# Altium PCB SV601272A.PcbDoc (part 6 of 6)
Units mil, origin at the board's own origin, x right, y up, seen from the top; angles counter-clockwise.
Board outline 8300 x 9520 mil, 8 copper layers (Top Layer, Signal Layer 1, Signal Layer 2, Signal Layer 3, Signal Layer 4, Signal Layer 5, Signal Layer 6, Bottom Layer), stack 59.2 mil thick; 551 components, 303 nets, 1611 pads, 1923 vias.

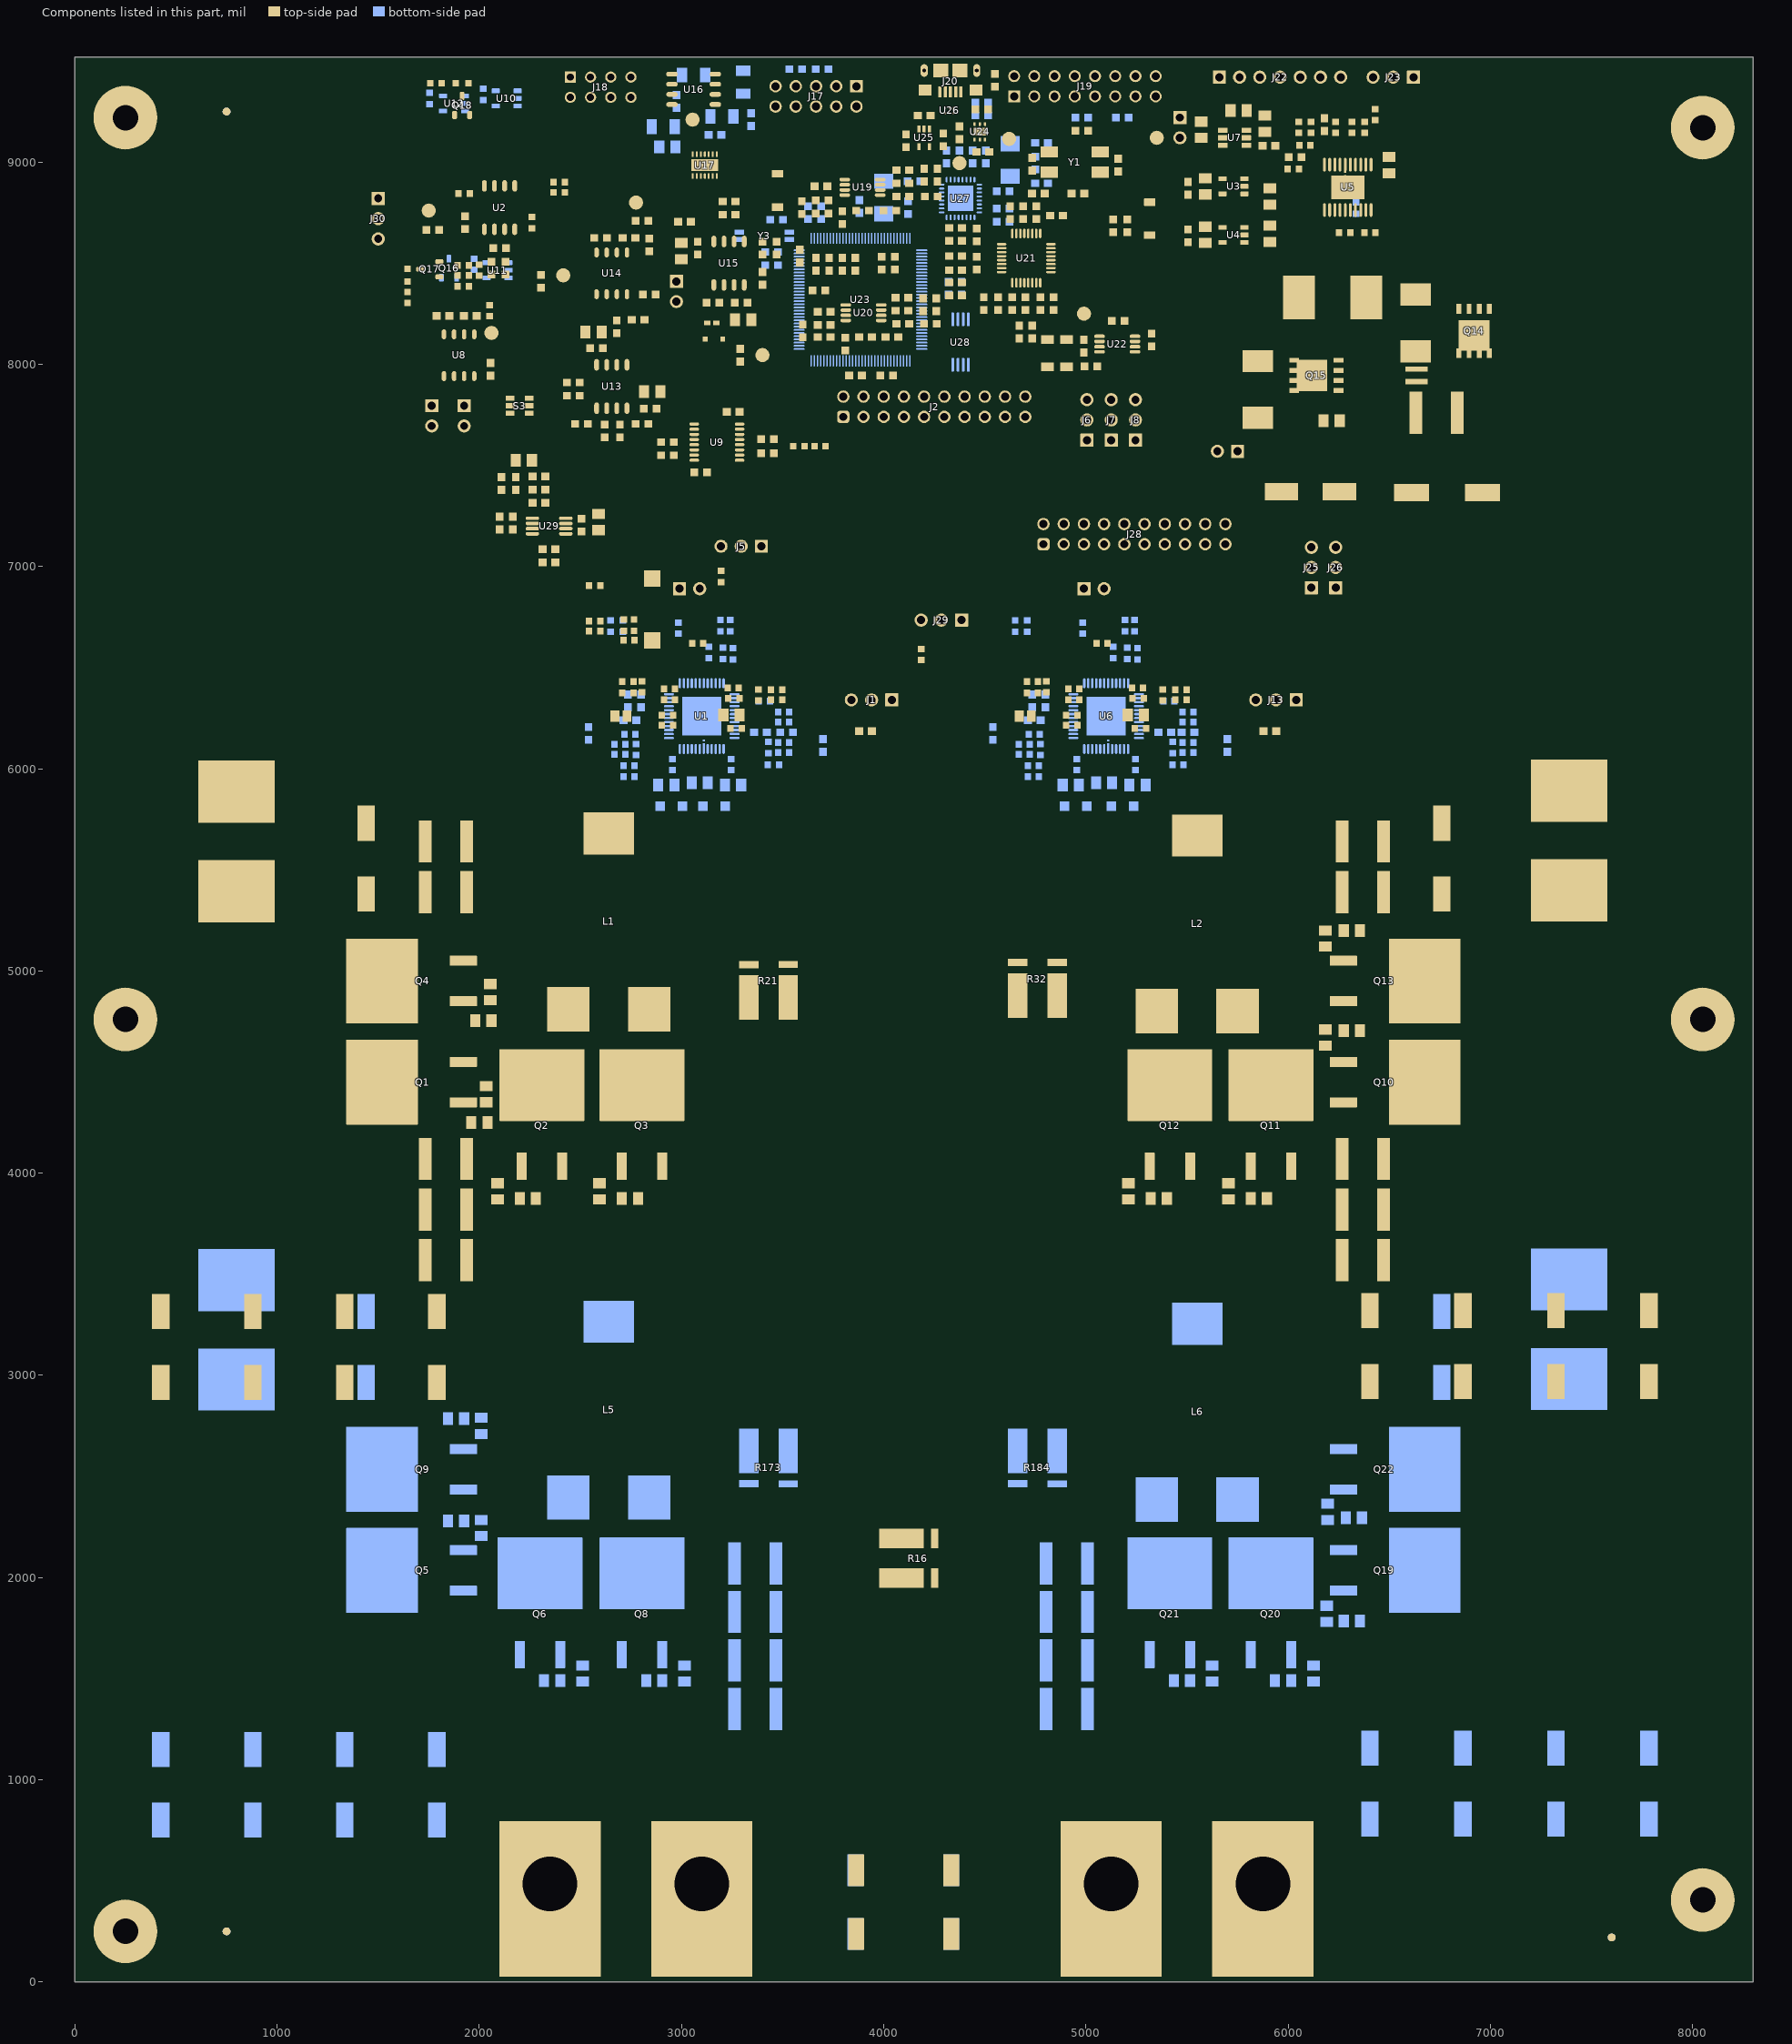
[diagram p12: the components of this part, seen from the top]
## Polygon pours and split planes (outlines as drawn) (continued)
NetC42_1 on Top Layer "NETC42_1_L01_P6041" (solid, remove dead copper, pour order 6041): 5715,7275 5715,7790 6200,7790 6200,7665 6200,7605 6070,7475 6065,7470 6065,7275
SW4 on Top Layer "SW4_L01_P6056" (solid, remove dead copper, pour order 6056): 5520,2735 5520,2285 5473.67,2238.67 5108.67,2238.67 5070,2200 5070,1865 5116.33,1818.67 6308.67,1818.67 6350,1860 6350,2745 6316.33,2778.67 5563.67,2778.67
SW3 on Top Layer "SW3_L01_P6058" (solid, remove dead copper, pour order 6058): 3180,1845 3180,2205 3143.26,2241.74 2716.74,2241.74 2670,2288.49 2670,2755 2653.26,2771.74 1886.74,2771.74 1850,2735 1850,1850 1888.26,1811.74 3146.74,1811.74
V_HV on Top Layer "V_HV_L01_P6060" (solid, remove dead copper, pour order 6060): 1840,945 1000,945 1000,3135 1840,3135
I_TOTAL on Top Layer "I_TOTAL_L01_P6053" (solid, remove dead copper, pour order 6053): 3460,4755 3460,5235 4730,5235 4730,4755
NetL5_1 on Top Layer "NETL5_1_L01_P6048" (solid, remove dead copper, pour order 6048): 2720,2275 3370,2275 3395,2300 3395,2740 3370,2765 2720,2765 2700,2745 2700,2295
V_LV on Top Layer "V_LV_L01_P6061" (solid, remove dead copper, pour order 6061): 5462,30.26 4699.74,30.26 4365,365 3800,365 3420,745 3420,2075 4885,2075 4885,1295 5462,718
AGND on Top Layer "AGND_L01_P6064" (solid, remove dead copper, pour order 6064): 2469.97,9500 1425,9500 1425,6070 6615,6070 6615,9500
PGND on Top Layer "PGND_L01_P6065" (solid, remove dead copper, pour order 6065): 0,0 0,9520 8320,9520 8320,0
V_LV on Signal Layer 3 "V_LV_L04_P6117" (solid, remove dead copper, pour order 6117): 3925,1565 4275,1565 4275,945 3925,945
V_HV on Signal Layer 3 "V_HV_L04_P6124" (solid, remove dead copper, pour order 6124): 8300,5850 6850,5850 6850,7525 6800,7575 6800,7920 6800,7945 6775,7970 6775,8240 8300,8240
V_HV on Signal Layer 3 "V_HV_L04_P6118" (solid, remove dead copper, pour order 6118): 7080,7215 6850,7215 6850,7520 6800,7570 6800,7915 6800,7940 6775,7965 6775,8235 7080,8235
SW4 on Signal Layer 3 "SW4_L04_P6120" (solid, remove dead copper, pour order 6120): 5495,2680 5495,2228.67 5113.67,2228.67 5070,2185 5070,1845 5106.33,1808.67 6133.67,1808.67 6170,1845 6170,2685 6135,2720 5535,2720
SW3 on Signal Layer 3 "SW3_L04_P6122" (solid, remove dead copper, pour order 6122): 3150,1845 3150,2215 3120,2245 2700,2245 2670,2275 2670,2695 2635,2730 2035,2730 2002.64,2697.64 2002.64,1842.36 2030,1815 3120,1815
SW2 on Signal Layer 3 "SW2_L04_P6121" (solid, remove dead copper, pour order 6121): 5495,5095 5495,4643.67 5113.67,4643.67 5070,4600 5070,4260 5106.33,4223.67 6133.67,4223.67 6170,4260 6170,5100 6135,5135 5535,5135
SW1 on Signal Layer 3 "SW1_L04_P6123" (solid, remove dead copper, pour order 6123): 3180,4250 3180,4620 3150,4650 2730,4650 2700,4680 2700,5100 2665,5135 2065,5135 2032.64,5102.64 2032.64,4247.36 2060,4220 3150,4220
I_TOTAL on Signal Layer 3 "I_TOTAL_L04_P6119" (solid, remove dead copper, pour order 6119): 3465,5235 4695,5235 4710,5220 4710,4755 3465,4755
V_HV on Signal Layer 3 "V_HV_L04_P6125" (solid, remove dead copper, pour order 6125): 0,0 0,5945 8300,5945 8300,67.21
PGND on Signal Layer 3 "PGND_L04_P6126" (solid, remove dead copper, pour order 6126): 5797.48,9495 7280,9495 7280,5965 0,5965 0,9495 2472.33,9495 1485,9495 1485,7905 2487.75,7905 3627.33,6765.42 3630.03,6768.12 4646.91,6768.12 4646.91,6770 5795.11,7918.19
AGND on Signal Layer 3 "AGND_L04_P6127" (solid, remove dead copper, pour order 6127): 2469.97,9500 1285,9500 1285,6070 6615,6070 6615,9500
V_LV on Signal Layer 4 "V_LV_L05_P6145" (solid, remove dead copper, pour order 6145): 3925,1555 4275,1555 4275,945 3925,945
V_HV on Signal Layer 4 "V_HV_L05_P6144" (solid, remove dead copper, pour order 6144): 6857.3,2740.55 6857.3,2330.55 6482.3,2330.55 6482.3,2740.55
V_HV on Signal Layer 4 "V_HV_L05_P6140" (solid, remove dead copper, pour order 6140): 6857.3,2240.55 6857.3,1830.55 6482.3,1830.55 6482.3,2240.55
V_HV on Signal Layer 4 "V_HV_L05_P6142" (solid, remove dead copper, pour order 6142): 1715,2240 1715,1830 1340,1830 1340,2240
V_HV on Signal Layer 4 "V_HV_L05_P6141" (solid, remove dead copper, pour order 6141): 1335.92,2329.37 1335.92,2739.37 1710.92,2739.37 1710.92,2329.37
SW3 on Signal Layer 4 "SW3_L05_P6135" (solid, remove dead copper, pour order 6135): 2114,2209 2476,2209 2500,2185 2500,1855 2479,1834 2111,1834 2090,1855 2090,2185
SW3 on Signal Layer 4 "SW3_L05_P6133" (solid, remove dead copper, pour order 6133): 2624,2209 2986,2209 3010,2185 3010,1855 2989,1834 2621,1834 2600,1855 2600,2185
SW4 on Signal Layer 4 "SW4_L05_P6129" (solid, remove dead copper, pour order 6129): 5735,2210 6095,2210 6120,2185 6120,1855 6100,1835 5730,1835 5710,1855 5710,2185
SW4 on Signal Layer 4 "SW4_L05_P6131" (solid, remove dead copper, pour order 6131): 5235,2210 5595,2210 5620,2185 5620,1855 5600,1835 5230,1835 5210,1855 5210,2185
DGND on Signal Layer 4 "DGND_L05_P6147" (solid, remove dead copper, pour order 6147): 4100,9420 4100,9270 3990,9270 3975,9255 3975,9220 3400,9220 3350,9170 3350,9070 3200,9070 3200,7895 4700,7895 4700,7970 4700,8620 4900,8620 4900,8770 5050,8770 5050,9270 4600,9270 4600,9420
NetD6_2 on Signal Layer 4 "Signal Layer 2-No Net 3" (solid, pour order 6128): 6215,7820 5750,7820 5750,8095 6215,8095
V_HV on Signal Layer 4 "V_HV_L05_P6146" (solid, remove dead copper, pour order 6146): 7074.74,7222.72 6844.74,7222.72 6844.74,7527.72 6794.74,7577.72 6794.74,7922.72 6794.74,7947.72 6769.74,7972.72 6769.74,8242.72 7074.74,8242.72
SW2 on Signal Layer 4 "SW2_L05_P6132" (solid, remove dead copper, pour order 6132): 5235,4625 5595,4625 5620,4600 5620,4270 5600,4250 5230,4250 5210,4270 5210,4600
SW2 on Signal Layer 4 "SW2_L05_P6130" (solid, remove dead copper, pour order 6130): 5735,4625 6095,4625 6120,4600 6120,4270 6100,4250 5730,4250 5710,4270 5710,4600
SW1 on Signal Layer 4 "SW1_L05_P6134" (solid, remove dead copper, pour order 6134): 2624,4624 2986,4624 3010,4600 3010,4270 2989,4249 2621,4249 2600,4270 2600,4600
SW1 on Signal Layer 4 "SW1_L05_P6136" (solid, remove dead copper, pour order 6136): 2114,4624 2476,4624 2500,4600 2500,4270 2479,4249 2111,4249 2090,4270 2090,4600
V_HV on Signal Layer 4 "V_HV_L05_P6138" (solid, remove dead copper, pour order 6138): 1335.92,4744.37 1335.92,5154.37 1710.92,5154.37 1710.92,4744.37
V_HV on Signal Layer 4 "V_HV_L05_P6143" (solid, remove dead copper, pour order 6143): 1715,4655 1715,4245 1340,4245 1340,4655
V_HV on Signal Layer 4 "V_HV_L05_P6139" (solid, remove dead copper, pour order 6139): 6857.3,4655.55 6857.3,4245.55 6482.3,4245.55 6482.3,4655.55
V_HV on Signal Layer 4 "V_HV_L05_P6137" (solid, remove dead copper, pour order 6137): 6857.3,5155.55 6857.3,4745.55 6482.3,4745.55 6482.3,5155.55
AGND on Signal Layer 4 "AGND_L05_P6148" (solid, remove dead copper, pour order 6148): 2469.97,9500 1425,9500 1425,6070 6615,6070 6615,9500
PGND on Signal Layer 4 "PGND_L05_P6149" (solid, remove dead copper, pour order 6149): 0,0 0,9520 8300,9520 8300,0
I_TOTAL on Signal Layer 6 "I_TOTAL_L07_P6182" (solid, remove dead copper, pour order 6182): 4675,5240 4675,2330 3855,2330 3855,5240
I_TOTAL on Signal Layer 6 "I_TOTAL_L07_P6181" (solid, remove dead copper, pour order 6181): 3460,2335 4725,2335 4730,2340 4730,2820 3460,2820
V_LV on Signal Layer 6 "V_LV_L07_P6179" (solid, remove dead copper, pour order 6179): 3925,2075 4275,2075 4275,1235 3925,1235
V_HV on Signal Layer 6 "V_HV_L07_P6178" (solid, remove dead copper, pour order 6178): 6855,5155 6855,4745 6480,4745 6480,5155
V_HV on Signal Layer 6 "V_HV_L07_P6172" (solid, remove dead copper, pour order 6172): 1710,4655 1710,4245 1335,4245 1335,4655
V_HV on Signal Layer 6 "V_HV_L07_P6175" (solid, remove dead copper, pour order 6175): 1715,5155 1715,4745 1340,4745 1340,5155
V_HV on Signal Layer 6 "V_HV_L07_P6173" (solid, remove dead copper, pour order 6173): 6858.58,4655 6858.58,4245 6483.58,4245 6483.58,4655
SW2 on Signal Layer 6 "SW2_L07_P6164" (solid, remove dead copper, pour order 6164): 5738.58,4618.58 6091.42,4618.58 6120,4590 6120,4270 6093.58,4243.58 5736.42,4243.58 5710,4270 5710,4590
SW2 on Signal Layer 6 "SW2_L07_P6165" (solid, remove dead copper, pour order 6165): 5238.58,4618.58 5591.42,4618.58 5620,4590 5620,4270 5593.58,4243.58 5236.42,4243.58 5210,4270 5210,4590
SW1 on Signal Layer 6 "SW1_L07_P6167" (solid, remove dead copper, pour order 6167): 2121.77,4616.77 2478.23,4616.77 2505,4590 2505,4265 2481.77,4241.77 2123.23,4241.77 2095,4270 2095,4590
SW1 on Signal Layer 6 "SW1_L07_P6170" (solid, remove dead copper, pour order 6170): 2625,4615 2985,4615 3010,4590 3010,4265 2985,4240 2625,4240 2600,4265 2600,4590
SW3 on Signal Layer 6 "SW3_L07_P6169" (solid, remove dead copper, pour order 6169): 2625,2200 2985,2200 3010,2175 3010,1850 2985,1825 2625,1825 2600,1850 2600,2175
SW3 on Signal Layer 6 "SW3_L07_P6168" (solid, remove dead copper, pour order 6168): 2121.77,2201.77 2478.23,2201.77 2505,2175 2505,1850 2481.77,1826.77 2123.23,1826.77 2095,1855 2095,2175
SW4 on Signal Layer 6 "SW4_L07_P6166" (solid, remove dead copper, pour order 6166): 5238.58,2203.58 5591.42,2203.58 5620,2175 5620,1855 5593.58,1828.58 5236.42,1828.58 5210,1855 5210,2175
SW4 on Signal Layer 6 "SW4_L07_P6163" (solid, remove dead copper, pour order 6163): 5738.58,2203.58 6091.42,2203.58 6120,2175 6120,1855 6093.58,1828.58 5736.42,1828.58 5710,1855 5710,2175
V_HV on Signal Layer 6 "V_HV_L07_P6171" (solid, remove dead copper, pour order 6171): 6858.58,2240 6858.58,1830 6483.58,1830 6483.58,2240
V_HV on Signal Layer 6 "V_HV_L07_P6176" (solid, remove dead copper, pour order 6176): 1715,2740 1715,2330 1340,2330 1340,2740
V_HV on Signal Layer 6 "V_HV_L07_P6174" (solid, remove dead copper, pour order 6174): 1710,2240 1710,1830 1335,1830 1335,2240
V_HV on Signal Layer 6 "V_HV_L07_P6177" (solid, remove dead copper, pour order 6177): 6855,2740 6855,2330 6480,2330 6480,2740
I_TOTAL on Signal Layer 6 "I_TOTAL_L07_P6180" (solid, remove dead copper, pour order 6180): 3460,4755 3460,5235 4730,5235 4730,4755
AGND on Signal Layer 6 "AGND_L07_P6183" (solid, remove dead copper, pour order 6183): 2469.97,9500 1425,9500 1425,6070 6615,6070 6615,9500
PGND on Signal Layer 6 "PGND_L07_P6184" (solid, remove dead copper, pour order 6184): 0,0 0,9520 8300,9520 8300,0
V_LV on Signal Layer 5 "V_LV_L06_P6154" (solid, remove dead copper, pour order 6154): 3925,1535 4275,1535 4275,955 3925,955
SW3 on Signal Layer 5 "SW3_L06_P6158" (solid, remove dead copper, pour order 6158): 3340,1845 3340,2195 3300,2235 2690,2235 2690,2665 2635,2720 2080,2720 2032.64,2672.64 2032.64,1862.36 2090,1805 3300,1805
SW4 on Signal Layer 5 "SW4_L06_P6156" (solid, remove dead copper, pour order 6156): 5510,2685 5510,2228.67 4993.67,2228.67 4950,2185 4950,1855 4996.33,1808.67 6123.67,1808.67 6170,1855 6170,2685 6130,2725 5550,2725
SW2 on Signal Layer 5 "SW2_L06_P6155" (solid, remove dead copper, pour order 6155): 5510,5100 5510,4643.67 4993.67,4643.67 4950,4600 4950,4270 4996.33,4223.67 6123.67,4223.67 6170,4270 6170,5100 6130,5140 5550,5140
SW1 on Signal Layer 5 "SW1_L06_P6157" (solid, remove dead copper, pour order 6157): 3340,4260 3340,4610 3300,4650 2690,4650 2690,5080 2635,5135 2080,5135 2032.64,5087.64 2032.64,4277.36 2090,4220 3300,4220
V_HV on Signal Layer 5 "V_HV_L06_P6150" (solid, remove dead copper, pour order 6150): 1711.28,4654.45 1711.28,4244.45 1336.28,4244.45 1336.28,4654.45
V_HV on Signal Layer 5 "Signal Layer 3-No Net 2" (solid, remove dead copper, pour order 6151): 1711.28,5154.45 1711.28,4744.45 1336.28,4744.45 1336.28,5154.45
V_HV on Signal Layer 5 "Signal Layer 3-No Net 2" (solid, remove dead copper, pour order 6153): 6855,4655 6855,4245 6480,4245 6480,4655
V_HV on Signal Layer 5 "Signal Layer 3-No Net 2" (solid, remove dead copper, pour order 6152): 6855,5155 6855,4745 6480,4745 6480,5155
V_HV on Signal Layer 5 "V_HV_L06_P6160" (solid, remove dead copper, pour order 6160): 7730,0 0,0 0,3070 7730,3070
V_HV on Signal Layer 5 "V_HV_L06_P6161" (solid, remove dead copper, pour order 6161): 8300,2615 0,2615 0,5685 8300,5685
AGND on Signal Layer 5 "AGND_L06_P6159" (solid, remove dead copper, pour order 6159): 2469.97,9500 1425,9500 1425,6070 6615,6070 6615,9500
PGND on Signal Layer 5 "PGND_L06_P6162" (solid, remove dead copper, pour order 6162): 0,-1055 0,9520 8300,9520 8300,-1055

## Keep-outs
Keep-Out Layer:
  lines w10: 0,0 8300,0 8300,9530 0,9530 0,0
  text ".Layer_Name" at -823,-3938.49 h60

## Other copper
Top Layer:
  rectangle net V_HV: 1650,5500 1840,5770
  rectangle net PGND: 6215,8815 6535,8940
  pour cut-out: 3450,2275 3400,2275 3400,2605 3450,2605 3450,2325
  pour cut-out: 4230,4690 3400,4690 3400,5005 3450,5005 3450,4740 4230,4740
  pour cut-out: 6625,7940 6645,7940 6655,7930 6655,7910 6645,7900 6625,7900 6615,7910 6615,7930
  pour cut-out: 6200,8705 6220,8705 6230,8695 6230,8675 6220,8665 6200,8665 6190,8675 6190,8695
  pour cut-out: 6230.97,8700.64 6220,8700.64 6220,8805 6236.74,8805 6245,8796.74 6245,8714.67
  pour cut-out: 2035,-40 2035,855 2670,855 2670,-40
  region net V_HV: 7030,7020 7030,7570 6850,7750 6850,7850 7210,7850 7210,7020
  region net PGND: 6150,7275 6700,7275 6700,7875 6325,7875 6275,7825 6225,7775 6225,7475 6200,7450 6150,7450
  pour cut-out: 3960,4695 4790,4695 4790,5010 4740,5010 4740,4745 3960,4745
  pour cut-out: 4790,2275 4740,2275 4740,2605 4790,2605 4790,2325
  text ".Layer_Name" at -823,-3938.49 h60
Signal Layer 1:
  pour cut-out: 6625,7940 6645,7940 6655,7930 6655,7910 6645,7900 6625,7900 6615,7910 6615,7930
  pour cut-out: 6200,8705 6220,8705 6230,8695 6230,8675 6220,8665 6200,8665 6190,8675 6190,8695
  text ".Layer_Name" at -825,-3935 h60
Signal Layer 2:
  pour cut-out: 6625,7940 6645,7940 6655,7930 6655,7910 6645,7900 6625,7900 6615,7910 6615,7930
  pour cut-out: 6200,8705 6220,8705 6230,8695 6230,8675 6220,8665 6200,8665 6190,8675 6190,8695
  text ".Layer_Name" at -825,-3935 h60
Signal Layer 3:
  rectangle net I_TOTAL: 3570,2360 4560,2760
  rectangle net AGND: 5000,6155 5200,6360
  rectangle net AGND: 3000,6155 3205,6360
  pour cut-out: 6625,7940 6645,7940 6655,7930 6655,7910 6645,7900 6625,7900 6615,7910 6615,7930
  pour cut-out: 6200,8705 6220,8705 6230,8695 6230,8675 6220,8665 6200,8665 6190,8675 6190,8695
  text ".Layer_Name" at -825,-3935 h60
Signal Layer 4:
  rectangle net I_TOTAL: 4400,2360 4560,2780
  rectangle net I_TOTAL: 3570,2360 3915,2755
  region: 1720,4862.56
  pour cut-out: 6625,7940 6645,7940 6655,7930 6655,7910 6645,7900 6625,7900 6615,7910 6615,7930
  pour cut-out: 6200,8705 6220,8705 6230,8695 6230,8675 6220,8665 6200,8665 6190,8675 6190,8695
  text ".Layer_Name" at -825,-3935 h60
Signal Layer 5:
  region net I_TOTAL: 4395,5235 4395,4705 4330,4640 4330,2095 4675,2095 4675,5235
  region net V_LV: 3925,955 4300,955 4300,1550 3925,1550
  region net I_TOTAL: 3900,2090 3575,2090 3575,5235 3900,5235
  pour cut-out: 6200,8705 6220,8705 6230,8695 6230,8675 6220,8665 6200,8665 6190,8675 6190,8695
  text ".layer_Name" at -820,-3940 h60
Signal Layer 6:
  region net V_LV: 3925,1215 4275,1215 4275,1550 3925,1550
  region net I_TOTAL: 3900,2330 3575,2330 3575,5240 3900,5240
  pour cut-out: 6200,8705 6220,8705 6230,8695 6230,8675 6220,8665 6200,8665 6190,8675 6190,8695
  text ".layer_Name" at -820,-3940 h60
Bottom Layer:
  rectangle net AGND: 5082.61,6143.07 5142.61,6168.07
  rectangle net AGND: 3082.61,6143.07 3142.61,6168.07
  region net I_TOTAL: 3900,2335 3585,2335 3585,5235 3900,5235
  region net V_LV: 3922.5,640 4297.5,640 4297.5,1550 3922.5,1550
  pour cut-out: 6625,7940 6645,7940 6655,7930 6655,7910 6645,7900 6625,7900 6615,7910 6615,7930
  pour cut-out: 6200,8705 6220,8705 6230,8695 6230,8675 6220,8665 6200,8665 6190,8675 6190,8695
  text ".Layer_Name" at -823,-3938.49 h60
Multi-Layer:
  region: 1670,2647.56
  region: 1670,5062.56

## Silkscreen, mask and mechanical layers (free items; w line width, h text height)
Top Overlay:
  rectangle: 1355,7360 1655,7460
  lines w8: 2785,6310 2840,6310 2855,6295 ; 2855,6295 2845.11,6295 2855,6304.89 2855,6295
  text "BUCK MODE" at 1635,9445 h28
  text "AGND" at 6730,9405 h72.83
  text "RESET" at 5600,9335 h40
  text "TDO" at 5725,9335 h40
  text "TDI" at 5830,9335 h40
  text "TMS" at 5925,9335 h40
  text "TCK" at 6025,9335 h40
  text "RX" at 6135,9335 h40
  text "TX" at 6240,9335 h40
  text "IREF" at 2375,9315 h72.83 r90
  text "VREF" at 2865,9285 h72.83 r90
  text "MISO" at 4605,9240 h40
  text "MOSI" at 4705,9240 h40
  text "CS" at 4820,9240 h40
  text "SCLK" at 4895,9240 h40
  text "DRDY" at 4995,9240 h40
  text "DONE" at 5100,9240 h40
  text "AGND" at 5205,9240 h40
  text "AGND" at 5315,9240 h35
  text "AGND" at 1435,8620 h72.83 r90
  text "CC" at 2955,8385 h28
  text "BOOST MODE" at 1555,8240 h28 r90
  text "V5A" at 1630,8140 h28 r90
  text "N" at 5365,7810 h28 r90
  text "BOOST" at 4910,7750 h28 r90
  text "NFAULT" at 3830,7650 h40
  text "SYNCOUT" at 4015,7650 h40
  text "ISETA" at 4250,7650 h40
  text "UVLO" at 4455,7650 h40
  text "OVPA" at 4655,7650 h40
  text "OPT" at 3750,7620 h40
  text "OVPB" at 4555,7620 h40
  text "IOUT2" at 4155,7615 h40
  text "SYNCIN" at 4330,7615 h40
  text "Y" at 5365,7615 h28 r90
  text "IOUT1" at 3955,7610 h40
  text "CV" at 1740,7585 h28
  text "BUCK" at 4910,7580 h28 r90
  text "VLV" at 1940,7545 h28 r90
  text "VHV" at 2095,7540 h28 r90
  text "DIR" at 4970,7500 h28
  text "EN1" at 5090,7500 h28
  text "EN2" at 5205,7500 h28
  text "V10-Aux" at 5600,7455 h28
  text "OPT" at 3025,7350 h28
  text "NFAULT2" at 4820,7020 h40
  text "SYNCOUT2" at 5005,7020 h40
  text "ISETA" at 5240,7020 h40
  text "UVLO" at 5445,7020 h40
  text "OVPA2" at 5645,7020 h40
  text "SYNC_OUT" at 2920,7010 h28
  text "OPT2" at 4740,6990 h40
  text "OVPB2" at 5545,6990 h40
  text "IOUT4" at 5145,6985 h40
  text "SYNCIN2" at 5320,6985 h40
  text "IOUT3" at 4945,6980 h40
  text "EN3" at 6080,6770 h28
  text "EN4" at 6195,6770 h28
  text "LV" at 5800,6415 h28
  text "HV" at 6020,6415 h28
  text "LV" at 3790,6410 h28
  text "UVLO" at 3885,6410 h28
  text "HV" at 4040,6410 h28
  text "V_HV" at 2580,3440 h80
  text "V_LV" at 5380,3435 h80
  text "-" at 3085,3390 h120
  text "+" at 2320,3385 h120
  text "-" at 5850,3385 h120
  text "+" at 5070,3370 h120
  text ".Layer_Name" at -823,-3938.49 h60
Bottom Overlay:
  text "J3" at 4150,7585 h28
  text "J5" at 3150,7440 h28
  text "OPT" at 3110,7350 h28
  text "J21" at 5210,6940 h28
  text "HV BIAS LV" at 6065,6415 h28
  text "HV VIN LV" at 4060,6410 h28
  text "J1" at 4155,6320 h28
  text "V_LV" at 5680,3445 h80
  text "V_HV" at 2880,3430 h80
  text "-" at 3165,3395 h120
  text "+" at 2400,3390 h120
  text "-" at 5935,3380 h120
  text "+" at 5155,3365 h120
  text ".Layer_Name" at -823,-3938.49 h60
Top Paste:
  text ".Layer_Name" at -823,-3938.49 h60
Bottom Paste:
  text ".Layer_Name" at -823,-3938.49 h60
Top Solder:
  text ".Layer_Name" at -823,-3938.49 h60
  text ".Layer_Name" at -823,-3938.49 h60
Bottom Solder:
  text ".Layer_Name" at -823,-3938.49 h60
Drill Guide:
  text ".Layer_Name" at -823,-3938.49 h60
M1 Board Outline:
  the board outline again, w10
  text ".Layer_Name" at -823,-3938.49 h60
M2 Board Dimensions:
  rectangle: -1275,-3480 -900,-3355
  rectangle: -1400,-3355 -1275,-3230
  lines w7: -1400,-3355 -400,-3355 ; -1275,-3480 -1275,-3230 ; -1150,-3480 -1150,-3230 ; -900,-3480 -900,-3230 ; -650,-3480 -650,-3230 ; -1400,-3480 -1400,-3230 -400,-3230 -400,-3480 -1400,-3480
  text ".Layer_Name" at -823,-3938.49 h60
M3 3D STEP Top:
  text ".Layer_Name" at -823,-3938.49 h60
M4 3D STEP Bottom:
  text ".Layer_Name" at -823,-3938.49 h60
M5 Assembly Top:
  lines w10: -1692,-4010.17 4908,-4010.17 ; -1692,-3806.83 4910,-3806.83 ; -1692,-3603.5 -1692,-4213.5 2313,-4213.5 4910,-4213.5 4910,-3603.5 -1691.5,-3603.5 -1691.5,-4213.5 -116,-4213.5 ; 773,-4213.5 773,-3603.5 ; 2040,-3806.83 2040,-3603.5 ; 2880,-3806.83 2880,-3603.5 ; 3502,-4220 3502,-4017.17
  text "COMPONENTS MARKED 'DNP' SHOULD NOT BE POPULATED." at -246.5,-3398.5 h60
  text "ASSEMBLY VARIANT:" at -247,-3514 h60
  text ".VariantName" at 789,-3514 h60
  text "PCB VIEWED FROM TOP SIDE" at -1628.5,-3735.67 h60
  text "BOARD #:" at 848,-3735.67 h60
  text ".PRJ_Number" at 1393.5,-3735.67 h60
  text "REV:" at 2238,-3735.67 h60
  text ".PCB_Rev" at 2529.5,-3735.67 h60
  text ".VersionControl_RevNumber" at 3582,-3735.67 h60
  text "SVN REV:" at 2313.19,-3776.26 h60
  text "PLOT NAME =" at -1628.5,-4144.34 h60
  text ".plot_File_Name" at -823,-4144.34 h60
  text "GENERATED    :" at 850,-4144.34 h60
  text ".Print_Date" at 1719.5,-4144.34 h60
  text ".Print_Time" at 2448.5,-4144.34 h60
  text "TEXAS INSTRUMENTS" at 3713,-4144.34 h60
M6 Assembly Bottom:
  lines w10: -1692.5,-3807.33 4909.5,-3807.33 ; -1690.5,-4010.67 4909.5,-4010.67 ; -284.5,-4220.5 -284.5,-4017.67 ; 337.5,-3807.33 337.5,-3604 ; 1177.5,-3807.33 1177.5,-3604 ; 2444.5,-4214 2444.5,-3604 ; 3333.5,-4214 4909,-4214 4909,-3604 -1692.5,-3604 -1692.5,-4214 904.5,-4214 4909.5,-4214 4909.5,-3604
  text "COMPONENTS MARKED 'DNP' SHOULD NOT BE POPULATED." at 4702,-3398 h60
  text ".VariantName" at 3658,-3514 h60
  text "ASSEMBLY VARIANT:" at 4697,-3514 h60
  text ".VersionControl_RevNumber" at -364.5,-3736.17 h60
  text "SVN REV:" at 141.5,-3736.17 h60
  text ".PCB_Rev" at 688,-3736.17 h60
  text "REV:" at 979.5,-3736.17 h60
  text ".PRJ_Number" at 1824,-3736.17 h60
  text "BOARD #:" at 2369.5,-3736.17 h60
  text "PCB VIEWED FROM BOTTOM SIDE" at 4846,-3736.17 h60
  text "TEXAS INSTRUMENTS" at -495.5,-4144.84 h60
  text ".Print_Time" at 769,-4144.84 h60
  text ".Print_Date" at 1498,-4144.84 h60
  text "GENERATED    :" at 2367.5,-4144.84 h60
  text ".plot_File_Name" at 4040.5,-4144.84 h60
  text "PLOT NAME =" at 4846,-4144.84 h60
M9 Title Sheet:
  drawing of 57 lines, arcs and shapes, not listed
  text "1" at -660.16,4956.5 h70
  text "2" at 1835.5,4956.5 h70
  text "3" at 4324.84,4956.5 h70
  text "4" at 4831.51,4956.5 h70
  text "5" at 7330.5,4956.5 h70
  text "6" at 9835.5,4956.5 h70
  text "A" at -1816.5,3813.5 h70
  text "A" at 12983.5,3813.5 h70
  text "B" at -1816.5,1433.5 h70
  text "B" at 12983.5,1433.5 h70
  text "C" at -1816.5,-941.5 h70
  text "C" at 12983.5,-941.5 h70
  text "PROJECT TITLE:" at 9943.5,-2802.5 h45
  text ".PRJ_Title" at 9993.5,-2935.83 h70
  text "DESIGNED FOR:" at 9943.5,-3103.5 h45
  text ".PRJ_Customer" at 9993.5,-3243.5 h70
  text "D" at -1816.5,-3311.5 h70
  text "D" at 12983.5,-3311.5 h70
  text "FILE NAME:" at 9943.5,-3403.5 h45
  text ".PCB_File_Name_No_Path" at 9993.5,-3523.5 h70
  text "Texas Instruments (TI) and/or its licensors do not warrant the accuracy or completeness of this specification" at 4974,-3685.34 h45
  text "ENGINEER:" at 9943.5,-3693.5 h45
  text "LAYOUT BY:" at 11448.5,-3693.5 h45
  text "or any information contained therein. TI and/or its licensors do not warrant that this design will meet" at 4929.01,-3798 h45
  text ".PRJ_Engineer" at 9993.5,-3848.49 h70
  text ".PCB_Layout" at 11499,-3848.49 h70
  text "the specifications, will be suitable for your application or fit for any particular purpose, or will operate in" at 4929.01,-3910.67 h45
  text ".Layer_Name" at -823,-3938.49 h60
  text "ALTIUM DESIGNER VERSION:" at 11448.5,-4003.5 h45
  text "an implementation. TI and/or its licensors do not warrant that the design is production worthy. You should" at 4929.01,-4023.33 h45
  text "completely validate and test your design implementation to confirm the system functionality for your application." at 4974,-4136 h45
  text ".print_Scale" at 9993.5,-4136.83 h70
  text ".Application_BuildNumber" at 11499,-4136.83 h70
  text "1" at -660.16,-4343.5 h70
  text "2" at 1835.5,-4343.5 h70
  text "3" at 4324.84,-4343.5 h70
  text "4" at 6831.51,-4343.5 h70
  text "5" at 9330.5,-4343.5 h70
  text "6" at 11835.5,-4343.5 h70
M10 Fab Notes:
  drawing of 185 lines, arcs and shapes, not listed
  text "DESIGN INFORMATION" at 10981.02,2830 h60
  text "MIN. TRACK WIDTH:" at 10336.46,2650 h60
  text "8" at 11432.7,2650 h60
  text "MIL" at 11587.46,2650 h60
  text "MIN. CLEARANCE:" at 10336.46,2518 h60
  text "0.2" at 11372.7,2518 h60
  text "mm" at 11587.46,2518 h60
  text "MIN. VIA PAD SIZE:" at 10336.46,2386 h60
  text "24" at 11402.71,2386 h60
  text "MIL" at 11587.46,2386 h60
  text "0.05mm (2MIL)" at 11031.46,2244.29 h60
  text "MINIMUM ANNULAR RING" at 10007.23,2240 h60
  text "EXTERNAL" at 11739.46,2240 h60
  text "PER" at 10207.23,2122 h60
  text "IPC-D-275 CLASS 2 LEVEL C" at 10427.23,2122 h60
  text "MIL, HOLES" at 11915.46,2009.71 h60
  text "+/-" at 11523,2009 h60
  text "+/-" at 12377,2009 h60
  text "REGISTRATION TOLERANCES:" at 10007.23,2004 h60
  text "METAL" at 11207,2004 h60
  text "5" at 11783.2,2004 h60
  text "3" at 12616.2,2004 h60
  text "MIL" at 12732.46,2004 h60
  text "MATERIAL:" at 9932.46,1794.54 h60
  text "FR-4 High Tg" at 10918.9,1654.21 h60
  text "FR-408" at 10353.46,1645.64 h60
  text "X" at 10765.46,1645.64 h60
  text "OTHER" at 11841.46,1645.64 h60
  text "62 MIL (1.6mm) +/-10%" at 10673.56,1482.92 h60
  text "THICKNESS:" at 10007.23,1478.64 h60
  text "X" at 10545.4,1478.64 h60
  text "OTHER" at 11958.46,1478.64 h60
  text "TOLERANCE:" at 8862.23,1320.64 h60
  text "X" at 10846.53,1320.64 h60
  text "ANSI IPC-6012 TYPE 3 CLASS 2" at 11033.48,1320.64 h60
  text "OTHER +/-" at 11033.46,1164.64 h60
  text "BOW & TWIST:" at 10007.23,1007.64 h60
  text "X" at 10846.53,1007.64 h60
  text "ANSI IPC-6012 TYPE 3 CLASS 2" at 11033.48,1007.64 h60
  text "OTHER +/-" at 11033.46,849.13 h60
  text "DRILLING:" at 9932.46,710.64 h60
  text "REFERENCE:" at 10007.23,593.64 h60
  text "X" at 10655.46,593.64 h60
  text "AS SHOWN" at 10842.46,593.64 h60
  text "X" at 11556.46,593.64 h60
  text "NC_DRILL FILES" at 11693.46,593.64 h60
  text "PTH MIN COPPER THICKNESS:" at 10007.23,435.64 h60
  text "X" at 11357.46,435.64 h60
  text "1MIL" at 11494.46,435.64 h60
  text "OTHER" at 11991.46,435.64 h60
  text "BOARD FINISH:" at 9932.46,276.64 h60
  text "SILKSCREEN:" at 10087.68,158.64 h60
  text "X" at 11036.46,158.64 h60
  text "TOP" at 11162.46,158.64 h60
  text "X" at 11546.46,158.64 h60
  text "BOTTOM" at 11673.46,158.64 h60
  text "SILKSCREEN COLOR:" at 10087.68,-8.36 h60
  text "X" at 11035.42,-8.36 h60
  text "WHITE" at 11162.46,-8.36 h60
  text "OTHER" at 11673.46,-8.36 h60
  text "SOLDER RESIST COLOR:" at 10087.68,-178.36 h60
  text "X" at 10655.42,-337.56 h60
  text "GREEN" at 10782.46,-337.56 h60
  text "BLUE" at 11373.46,-337.56 h60
  text "OTHER" at 11911.46,-337.56 h60
  text "IMMERSION GOLD (ENIG)" at 10993.46,-526.08 h60
  text "ENEPIG" at 12331,-529.36 h60
  text "SURFACE FINISH:" at 9932.46,-530.36 h60
  text "X" at 10805,-535 h60
  text "IMM. TIN/SILVER OR EQUIV" at 10262,-687.36 h60
  text "OTHER" at 11693.46,-687.36 h60
  text "ARRAY/PANEL:" at 9932.46,-866.36 h60
  text "CUT AND TRIM PER MECH LAYER 1" at 10993.46,-870.65 h60
  text "N.C. ROUTE" at 10993.46,-1022.36 h60
  text "V. SCORE" at 11859.46,-1022.36 h60
  text "X" at 10800,-1025 h60
  text "CERTIFICATION:" at 9932.46,-1159.36 h60
  text "MATERIALS AND WORKMANSHIP FOR ALL PCBS" at 10657.46,-1159.36 h60
  text "TO MEET OR EXCEED THE REQUIREMENTS OF:" at 10657.46,-1257.36 h60
  text "X" at 10283.96,-1393.87 h60
  text "ANSI IPC-A-600F CLASS ->" at 10422.96,-1393.87 h60
  text "X" at 12062.02,-1393.87 h60
  text "2" at 12180.96,-1393.86 h60
  text "1" at 11865.96,-1395.36 h60
  text "3" at 12534.96,-1395.36 h60
  text "X" at 10286.02,-1553.36 h60
  text "UL 94V-0" at 10422.96,-1553.36 h60
  text "X" at 11098.02,-1553.36 h60
  text "RoHS" at 11234.96,-1553.36 h60
  text "OTHER" at 11879.36,-1553.36 h60
  text "PER ORDER" at 12276.42,-1553.36 h60
  text "ADDITIONAL REQUIREMENTS:" at 9932.46,-1694.36 h60
  text "MICROSECTION:" at 10007.23,-1809.36 h60
  text "YES" at 10912.96,-1809.36 h60
  text "REQUIRED" at 11774.46,-1965.51 h60
  text "BARE BOARD ELEC. TEST:" at 10007.23,-1968.36 h60
  text "NONE" at 11312.96,-1968.36 h60
  text "X" at 11647.46,-1968.36 h60
  text "PER ORDER" at 12366.46,-1968.36 h60
  text "MANUFACTURER'S UL:" at 10007.23,-2125.36 h60
  text "RAIL" at 11172.96,-2129.65 h60
  text "METAL" at 11664.77,-2129.65 h60
  text "X" at 12040,-2130 h60
  text "SILK" at 12176.46,-2129.65 h60
  text ".Layer_Name" at -823,-3938.49 h60
M11 Gerber Information:
  lines w10: -1692,-4010.17 4908,-4010.17 ; -1692,-3806.83 4910,-3806.83 ; -1692,-3603.5 -1692,-4213.5 2313,-4213.5 4910,-4213.5 4910,-3603.5 -1691.5,-3603.5 -1691.5,-4213.5 -116,-4213.5 ; 773,-4213.5 773,-3603.5 ; 2040,-3806.83 2040,-3603.5 ; 2880,-3806.83 2880,-3603.5 ; 3502,-4220 3502,-4017.17
  text "ALL ARTWORK VIEWED FROM TOP SIDE" at -1628.5,-3735.67 h60
  text "BOARD #:" at 848,-3735.67 h60
  text ".PRJ_Number" at 1393.5,-3735.67 h60
  text "REV:" at 2238,-3735.67 h60
  text ".PCB_Rev" at 2529.5,-3735.67 h60
  text ".VersionControl_RevNumber" at 3582,-3735.67 h60
  text "SVN REV:" at 2313.19,-3776.26 h60
  text "LAYER NAME =" at -1628.5,-3938.49 h60
  text "PLOT NAME =" at -1628.5,-4144.34 h60
  text ".plot_File_Name" at -823,-4144.34 h60
  text "GENERATED    :" at 850,-4144.34 h60
  text ".Print_Date" at 1719.5,-4144.34 h60
  text ".Print_Time" at 2448.5,-4144.34 h60
  text "TEXAS INSTRUMENTS" at 3713,-4144.34 h60
M12 Stackup:
  drawing of 503 lines, arcs and shapes, not listed
  text "Layer" at -484.42,12885 h60
  text "Name" at -74.51,12885 h60
  text "Material" at 865.23,12885 h60
  text "Thickness" at 1725,12885 h60
  text "Constant" at 2374.84,12885 h60
  text "Board Layer Stack" at 2944.7,12885 h60
  text "1" at -484.42,12765 h60
  text "Top Overlay" at -74.51,12765 h60
  text "2" at -484.42,12645 h60
  text "Top Solder" at -74.51,12645 h60
  text "Solder Resist" at 865.23,12645 h60
  text "0.40mil" at 1725,12645 h60
  text "3.5" at 2374.84,12645 h60
  text "3" at -484.42,12525 h60
  text "Top Layer" at -74.51,12525 h60
  text "Copper" at 865.23,12525 h60
  text "3.20mil" at 1725,12525 h60
  text "4" at -484.42,12405 h60
  text "Dielectric1" at -74.51,12405 h60
  text "FR-4" at 865.23,12405 h60
  text "5.00mil" at 1725,12405 h60
  text "4.8" at 2374.84,12405 h60
  text "5" at -484.42,12285 h60
  text "Signal Layer 1" at -74.51,12285 h60
  text "Copper" at 865.23,12285 h60
  text "2.80mil" at 1725,12285 h60
  text "6" at -484.42,12165 h60
  text "Dielectric 2" at -74.51,12165 h60
  text "FR-4" at 865.23,12165 h60
  text "5.00mil" at 1725,12165 h60
  text "4.2" at 2374.84,12165 h60
  text "7" at -484.42,12045 h60
  text "Signal Layer 2" at -74.51,12045 h60
  text "Copper" at 865.23,12045 h60
  text "2.80mil" at 1725,12045 h60
  text "8" at -484.42,11925 h60
  text "Dielectric 3" at -74.51,11925 h60
  text "FR-4" at 865.23,11925 h60
  text "5.00mil" at 1725,11925 h60
  text "4.2" at 2374.84,11925 h60
  text "9" at -484.42,11805 h60
  text "Signal Layer 3" at -74.51,11805 h60
  text "Copper" at 865.23,11805 h60
  text "2.80mil" at 1725,11805 h60
  text "10" at -484.42,11685 h60
  text "Dielectric4" at -74.51,11685 h60
  text "FR-4" at 865.23,11685 h60
  text "6.00mil" at 1725,11685 h60
  text "4.2" at 2374.84,11685 h60
  text "11" at -484.42,11565 h60
  text "Signal Layer 4" at -74.51,11565 h60
  text "Copper" at 865.23,11565 h60
  text "2.80mil" at 1725,11565 h60
  text "12" at -484.42,11445 h60
  text "Dielectric 5" at -74.51,11445 h60
  text "FR-4" at 865.23,11445 h60
  text "5.00mil" at 1725,11445 h60
  text "4.2" at 2374.84,11445 h60
  text "13" at -484.42,11325 h60
  text "Signal Layer 5" at -74.51,11325 h60
  text "Copper" at 865.23,11325 h60
  text "2.80mil" at 1725,11325 h60
  text "14" at -484.42,11205 h60
  text "Dielectric 6" at -74.51,11205 h60
  text "FR-4" at 865.23,11205 h60
  text "5.00mil" at 1725,11205 h60
  text "4.2" at 2374.84,11205 h60
  text "15" at -484.42,11085 h60
  text "Signal Layer 6" at -74.51,11085 h60
  text "Copper" at 865.23,11085 h60
  text "2.80mil" at 1725,11085 h60
  text "16" at -484.42,10965 h60
  text "Dielectric 7" at -74.51,10965 h60
  text "FR-4" at 865.23,10965 h60
  text "5.00mil" at 1725,10965 h60
  text "4.2" at 2374.84,10965 h60
  text "17" at -484.42,10845 h60
  text "Bottom Layer" at -74.51,10845 h60
  text "Copper" at 865.23,10845 h60
  text "3.20mil" at 1725,10845 h60
  text "18" at -484.42,10725 h60
  text "Bottom Solder" at -74.51,10725 h60
  text "Solder Resist" at 865.23,10725 h60
  text "0.40mil" at 1725,10725 h60
  text "3.5" at 2374.84,10725 h60
  text "19" at -484.42,10605 h60
  text "Bottom Overlay" at -74.51,10605 h60
  text ".Layer_Name" at -823,-3938.49 h60
M13 Component Bodies Top:
  text ".Layer_Name" at -823,-3938.49 h60
M14 Component Bodies Bottom:
  text ".Layer_Name" at -823,-3938.49 h60
M15 Courtyards Top:
  text ".Layer_Name" at -823,-3938.49 h60
M16 Courtyards Bottom:
  text ".Layer_Name" at -823,-3938.49 h60
Drill Drawing:
  circle w10: c5783.72,12092.65 r16.58
  circle w10: c5783.72,12092.65 r27.63
  circle w10: c5783.72,11844.01 r27.63
  lines w10: 5756.09,10946.14 5756.09,10959.96 5769.9,10973.77 5756.09,10987.58 5756.09,11001.4 5769.9,11001.4 5783.72,10987.58 5797.53,11001.4 5811.34,11001.4 5811.34,10987.58 5797.53,10973.77 5811.34,10959.96 5811.34,10946.14 5797.53,10946.14 5783.72,10959.96 5769.9,10946.14 5756.09,10946.14 ; 5756.09,11084.28 5769.9,11084.28 5769.9,11070.46 5797.53,11070.46 5797.53,11084.28 5811.34,11084.28 5811.34,11111.9 5797.53,11111.9 5797.53,11125.72 5769.9,11125.72 5769.9,11111.9 5756.09,11111.9 5756.09,11084.28 ; 5756.09,11208.6 5769.9,11208.6 5783.72,11194.78 5797.53,11208.6 5811.34,11208.6 5797.53,11222.41 5811.34,11236.22 5797.53,11236.22 5783.72,11250.04 5769.9,11236.22 5756.09,11236.22 5769.9,11222.41 5756.09,11208.6 ; 5756.09,11332.92 5769.9,11332.92 5769.9,11319.1 5797.53,11319.1 5797.53,11332.92 5811.34,11332.92 5811.34,11360.54 5797.53,11360.54 5797.53,11374.36 5769.9,11374.36 5769.9,11360.54 5756.09,11360.54 5756.09,11332.92 ; 5756.09,11443.42 5811.34,11443.42 5811.34,11498.68 5756.09,11498.68 5756.09,11443.42 ; 5756.09,11623 5811.34,11623 5783.72,11567.74 5756.09,11623 ; 5756.09,11692.06 5783.72,11705.88 5811.34,11692.06 5797.53,11719.69 5811.34,11747.32 5783.72,11733.5 5756.09,11747.32 5769.9,11719.69 5756.09,11692.06 ; 5756.09,11940.7 5811.34,11940.7 5811.34,11995.96 5756.09,11995.96 5756.09,11940.7 ; 5756.09,12341.29 5783.72,12313.66 5811.34,12341.29 5783.72,12368.92 5756.09,12341.29 ; 5756.09,12686.62 5756.09,12700.44 5769.9,12714.25 5756.09,12728.06 5756.09,12741.88 5769.9,12741.88 5783.72,12728.06 5797.53,12741.88 5811.34,12741.88 5811.34,12728.06 5797.53,12714.25 5811.34,12700.44 5811.34,12686.62 5797.53,12686.62 5783.72,12700.44 5769.9,12686.62 5756.09,12686.62 ; 5767.14,11338.44 5775.43,11338.44 5775.43,11330.15 5792.01,11330.15 5792.01,11338.44 5800.29,11338.44 5800.29,11355.02 5792.01,11355.02 5792.01,11363.3 5775.43,11363.3 5775.43,11355.02 5767.14,11355.02 5767.14,11338.44 ; 5767.14,11951.75 5800.29,11951.75 5800.29,11984.9 5767.14,11984.9 5767.14,11951.75 ; 5767.14,12697.67 5767.14,12705.96 5775.43,12714.25 5767.14,12722.54 5767.14,12730.82 5775.43,12730.82 5783.72,12722.54 5792.01,12730.82 5800.29,12730.82 5800.29,12722.54 5792.01,12714.25 5800.29,12705.96 5800.29,12697.67 5792.01,12697.67 5783.72,12705.96 5775.43,12697.67 5767.14,12697.67
  lines w12: 5706,10908.85 7684.19,10908.85 ; 5706,12773.65 7684.19,12773.65 ; 6043.86,10784.53 6043.86,12897.97 ; 6376.03,10784.53 6376.03,12897.97 ; 7012.59,10784.53 7012.59,12897.97 ; 7271.73,10784.53 7271.73,12897.97 ; 5706,10784.53 7684.19,10784.53 7684.19,12897.97 5706,12897.97 5706,10784.53
  text "Symbol" at 5780.59,12810.94 h72
  text "Quantity" at 6081.16,12810.94 h72
  text "Finished Hole Size" at 6413.33,12810.94 h72
  text "Plated" at 7049.89,12810.94 h72
  text "Hole Type" at 7309.03,12810.94 h72
  text "70" at 6081.16,12686.62 h60
  text "7.87mil (0.200mm)" at 6413.33,12686.62 h60
  text "PTH" at 7049.89,12686.62 h60
  text "Round" at 7309.03,12686.62 h60
  text "785" at 6081.16,12562.3 h60
  text "8.00mil (0.203mm)" at 6413.33,12562.3 h60
  text "PTH" at 7049.89,12562.3 h60
  text "Round" at 7309.03,12562.3 h60
  text "C" at 5755.31,12552.31 h55.25
  text "201" at 6081.16,12437.98 h60
  text "10.00mil (0.254mm)" at 6413.33,12437.98 h60
  text "PTH" at 7049.89,12437.98 h60
  text "Round" at 7309.03,12437.98 h60
  text "B" at 5755.31,12427.99 h55.25
  text "2" at 6081.16,12313.66 h60
  text "12.00mil (0.305mm)" at 6413.33,12313.66 h60
  text "PTH" at 7049.89,12313.66 h60
  text "Round" at 7309.03,12313.66 h60
  text "859" at 6081.16,12189.34 h60
  text "16.00mil (0.406mm)" at 6413.33,12189.34 h60
  text "PTH" at 7049.89,12189.34 h60
  text "Round" at 7309.03,12189.34 h60
  text "A" at 5755.31,12179.35 h55.25
  text "2" at 6081.16,12065.02 h60
  text "20.00mil (0.508mm)" at 6413.33,12065.02 h60
  text "PTH" at 7049.89,12065.02 h60
  text "Round" at 7309.03,12065.02 h60
  text "4" at 6081.16,11940.7 h60
  text "28.00mil (0.711mm)" at 6413.33,11940.7 h60
  text "PTH" at 7049.89,11940.7 h60
  text "Round" at 7309.03,11940.7 h60
  text "8" at 6081.16,11816.38 h60
  text "35.43mil (0.900mm)" at 6413.33,11816.38 h60
  text "PTH" at 7049.89,11816.38 h60
  text "Round" at 7309.03,11816.38 h60
  text "16" at 6081.16,11692.06 h60
  text "39.37mil (1.000mm)" at 6413.33,11692.06 h60
  text "PTH" at 7049.89,11692.06 h60
  text "Round" at 7309.03,11692.06 h60
  text "94" at 6081.16,11567.74 h60
  text "40.00mil (1.016mm)" at 6413.33,11567.74 h60
  text "PTH" at 7049.89,11567.74 h60
  text "Round" at 7309.03,11567.74 h60
  text "10" at 6081.16,11443.42 h60
  text "40.16mil (1.020mm)" at 6413.33,11443.42 h60
  text "PTH" at 7049.89,11443.42 h60
  text "Round" at 7309.03,11443.42 h60
  text "6" at 6081.16,11319.1 h60
  text "125.98mil (3.200mm)" at 6413.33,11319.1 h60
  text "PTH" at 7049.89,11319.1 h60
  text "Round" at 7309.03,11319.1 h60
  text "4" at 6081.16,11194.78 h60
  text "254.00mil (6.452mm)" at 6413.33,11194.78 h60
  text "PTH" at 7049.89,11194.78 h60
  text "Round" at 7309.03,11194.78 h60
  text "4" at 6081.16,11070.46 h60
  text "270.00mil (6.858mm)" at 6413.33,11070.46 h60
  text "PTH" at 7049.89,11070.46 h60
  text "Round" at 7309.03,11070.46 h60
  text "2" at 6081.16,10946.14 h60
  text "19.69mil (0.500mm)" at 6413.33,10946.14 h60
  text "PTH" at 7049.89,10946.14 h60
  text "Slot" at 7309.03,10946.14 h60
  text "2067 Total" at 6081.16,10821.82 h60
  text "Slot definitions :" at 5780.59,10734.8 h60
  text "Routed Path Length" at 6231.31,10734.8 h60
  text "= Calculated from tool start centre position to tool end centre position." at 6771.05,10734.8 h60
  text "Hole Length" at 6231.31,10685.07 h60
  text "= Routed Path Length + Tool Size = Slot length as defined in the PCB layout" at 6571.25,10685.07 h60
  text ".Layer_Name" at -823,-3938.49 h60

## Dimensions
-1400,-3480 to -400,-3480 on M2 Board Dimensions
0,0 to 8300,0 on M2 Board Dimensions
0,0 to 0,9520 on M2 Board Dimensions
